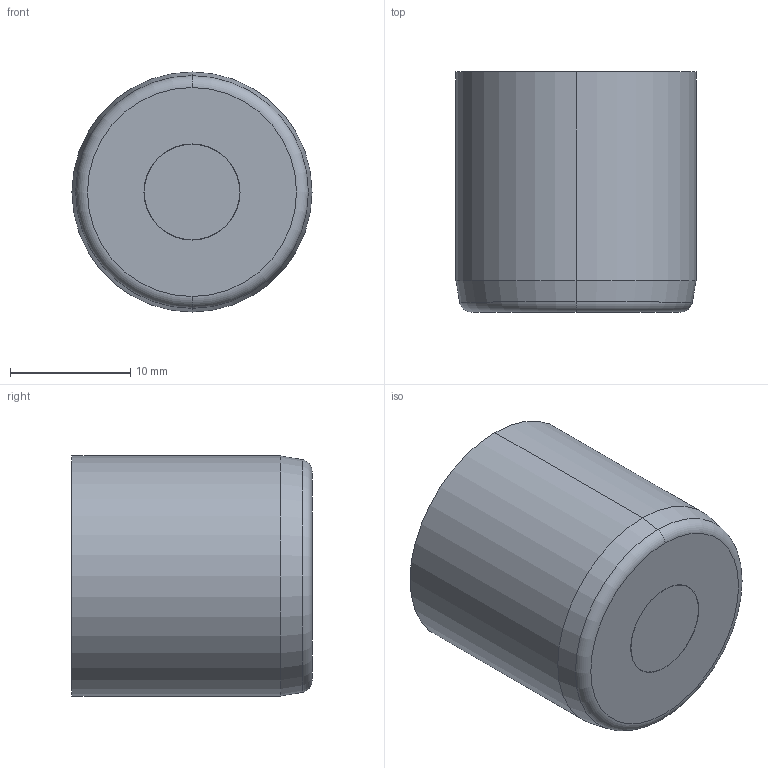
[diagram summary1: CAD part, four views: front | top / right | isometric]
STEP (ISO 10303-21) file: header records copied from the file, then geometry measured from it (millimetres).
FILE_DESCRIPTION (( 'STEP AP214' ), '1' );
FILE_NAME ('FA2007SF.STEP', '2013-06-28T08:10:47', ( '' ), ( '' ), 'SwSTEP 2.0', 'SolidWorks 2011', '' );
FILE_SCHEMA (( 'AUTOMOTIVE_DESIGN' ));
Length unit declared in the file: millimetre
Products named in the file (6): FA2007SF; FA 168700-3; FA 168700-2 comprimido; IA 1007SF; 9FA 042212; FA 168700-1
Assembly tree (5 placements, depth 2):
  FA2007SF
    9FA 042212
    FA 168700-2 comprimido
    IA 1007SF
    FA 168700-3
    FA 168700-1
Bounding box: 20 x 20 x 20 mm (x, y, z)
Volume: 6007.4 mm3; surface area: 3296.4 mm2
Topology: 5 solids, 5 shells, 310 faces, 784 edges, 509 vertices
Faces by surface type: plane 133, cylinder 131, cone 34, torus 10, bspline 2
Entity records: 10918 total; most frequent: CARTESIAN_POINT 2935, DIRECTION 1698, ORIENTED_EDGE 1564, EDGE_CURVE 782, AXIS2_PLACEMENT_3D 632, VERTEX_POINT 509, VECTOR 434, LINE 434
One B-rep face of a CAD part: STEP entity #7589.
In plain terms, the cylindrical face has radius 10 mm (diameter 20 mm), a partial arc.
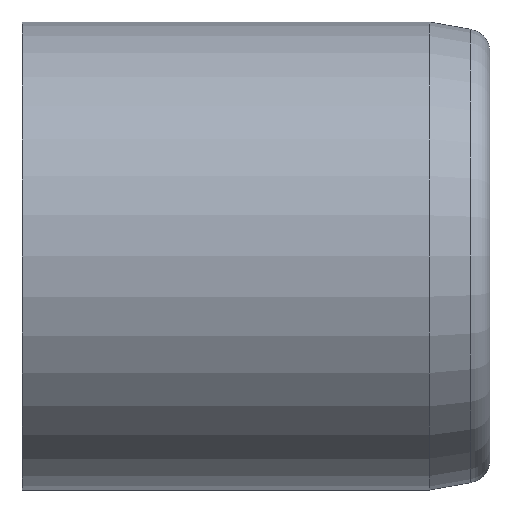
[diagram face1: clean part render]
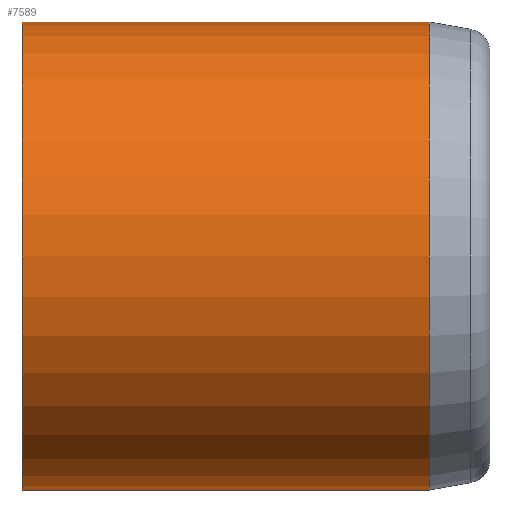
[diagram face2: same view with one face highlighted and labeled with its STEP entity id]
Its self-contained STEP definition (entity closure, numbers rounded to 3 decimals):
#254 = ORIENTED_EDGE ( 'NONE', *, *, #9442, .T. ) ;
#265 = ORIENTED_EDGE ( 'NONE', *, *, #9453, .F. ) ;
#283 = ORIENTED_EDGE ( 'NONE', *, *, #9445, .F. ) ;
#327 = ORIENTED_EDGE ( 'NONE', *, *, #9447, .T. ) ;
#569 = EDGE_LOOP ( 'NONE', ( #265, #283, #254, #327 ) ) ;
#2512 = CARTESIAN_POINT ( 'NONE',  ( 0., 20.13, 10. ) ) ;
#2589 = FACE_OUTER_BOUND ( 'NONE', #569, .T. ) ;
#2592 = CARTESIAN_POINT ( 'NONE',  ( 0., -9.8, 0. ) ) ;
#2599 = CYLINDRICAL_SURFACE ( 'NONE', #10995, 10. ) ;
#2602 = DIRECTION ( 'NONE',  ( 0., 0., 1. ) ) ;
#2616 = DIRECTION ( 'NONE',  ( 0., 1., 0. ) ) ;
#4313 = LINE ( 'NONE', #4334, #9146 ) ;
#4315 = DIRECTION ( 'NONE',  ( 0., 1., 0. ) ) ;
#4334 = CARTESIAN_POINT ( 'NONE',  ( 0., -9.8, 10. ) ) ;
#4363 = DIRECTION ( 'NONE',  ( 0., -1., 0. ) ) ;
#4366 = DIRECTION ( 'NONE',  ( 0., -1., 0. ) ) ;
#4370 = DIRECTION ( 'NONE',  ( 0., 0., 1. ) ) ;
#4373 = DIRECTION ( 'NONE',  ( 0., 1., 0. ) ) ;
#4374 = DIRECTION ( 'NONE',  ( 0., 0., -1. ) ) ;
#4383 = CARTESIAN_POINT ( 'NONE',  ( 0., -9.8, -10. ) ) ;
#4387 = CARTESIAN_POINT ( 'NONE',  ( 0., 2.73, 0. ) ) ;
#4389 = CARTESIAN_POINT ( 'NONE',  ( 0., 20.13, 0. ) ) ;
#4390 = LINE ( 'NONE', #4383, #9108 ) ;
#4547 = CARTESIAN_POINT ( 'NONE',  ( 0., 2.73, -10. ) ) ;
#4566 = CARTESIAN_POINT ( 'NONE',  ( 0., 2.73, 10. ) ) ;
#4592 = CARTESIAN_POINT ( 'NONE',  ( 0., 20.13, -10. ) ) ;
#7589 = ADVANCED_FACE ( 'NONE', ( #2589 ), #2599, .T. ) ;
#9100 = CIRCLE ( 'NONE', #9134, 10. ) ;
#9108 = VECTOR ( 'NONE', #4373, 1000. ) ;
#9110 = AXIS2_PLACEMENT_3D ( 'NONE', #4387, #4366, #4374 ) ;
#9131 = CIRCLE ( 'NONE', #9110, 10. ) ;
#9134 = AXIS2_PLACEMENT_3D ( 'NONE', #4389, #4363, #4370 ) ;
#9146 = VECTOR ( 'NONE', #4315, 1000. ) ;
#9442 = EDGE_CURVE ( 'NONE', #10185, #10251, #4313, .T. ) ;
#9445 = EDGE_CURVE ( 'NONE', #10185, #10189, #9131, .T. ) ;
#9447 = EDGE_CURVE ( 'NONE', #10251, #10219, #9100, .T. ) ;
#9453 = EDGE_CURVE ( 'NONE', #10189, #10219, #4390, .T. ) ;
#10185 = VERTEX_POINT ( 'NONE', #4566 ) ;
#10189 = VERTEX_POINT ( 'NONE', #4547 ) ;
#10219 = VERTEX_POINT ( 'NONE', #4592 ) ;
#10251 = VERTEX_POINT ( 'NONE', #2512 ) ;
#10995 = AXIS2_PLACEMENT_3D ( 'NONE', #2592, #2616, #2602 ) ;
